VERSION 5.7 ;
  NOWIREEXTENSIONATPIN ON ;
  DIVIDERCHAR "/" ;
  BUSBITCHARS "[]" ;

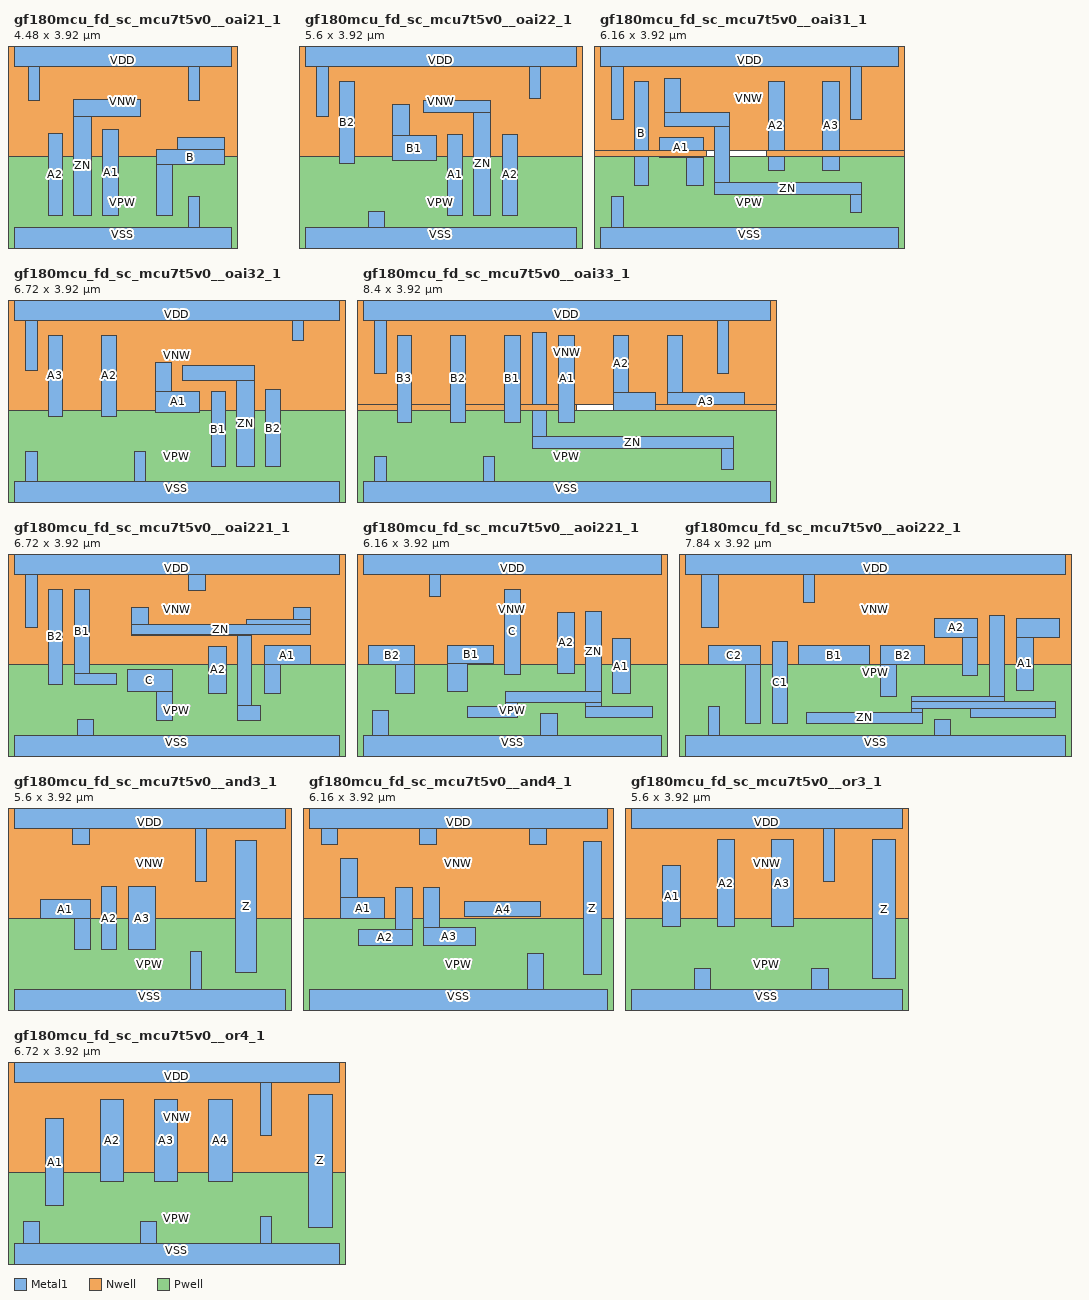
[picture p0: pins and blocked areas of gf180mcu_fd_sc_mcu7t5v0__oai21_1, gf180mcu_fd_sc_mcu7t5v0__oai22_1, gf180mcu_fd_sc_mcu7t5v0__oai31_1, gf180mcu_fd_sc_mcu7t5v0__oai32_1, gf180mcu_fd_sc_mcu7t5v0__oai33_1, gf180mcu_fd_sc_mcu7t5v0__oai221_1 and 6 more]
MACRO gf180mcu_fd_sc_mcu7t5v0__oai21_1
  CLASS core ;
  FOREIGN gf180mcu_fd_sc_mcu7t5v0__oai21_1 ;
  ORIGIN 0.000 0.000 ;
  SIZE 4.480 BY 3.920 ;
  SYMMETRY X Y ;
  SITE unithd ;
  PIN A1
    DIRECTION INPUT ;
    ANTENNAGATEAREA 1.102000 ;
    PORT
      LAYER Metal1 ;
        RECT 1.825 0.550 2.160 2.320 ;
    END
  END A1
  PIN A2
    DIRECTION INPUT ;
    ANTENNAGATEAREA 1.102000 ;
    PORT
      LAYER Metal1 ;
        RECT 0.705 0.550 1.000 2.230 ;
    END
  END A2
  PIN B
    DIRECTION INPUT ;
    ANTENNAGATEAREA 1.057000 ;
    PORT
      LAYER Metal1 ;
        RECT 3.375 1.900 4.350 2.150 ;
        RECT 2.945 1.600 4.350 1.900 ;
        RECT 2.945 0.550 3.280 1.600 ;
    END
  END B
  PIN ZN
    DIRECTION OUTPUT ;
    ANTENNADIFFAREA 1.276000 ;
    PORT
      LAYER Metal1 ;
        RECT 1.230 2.590 2.615 2.930 ;
        RECT 1.230 0.550 1.595 2.590 ;
    END
  END ZN
  PIN VDD
    DIRECTION INOUT ;
    USE POWER ;
    SHAPE ABUTMENT ;
    PORT
      LAYER Metal1 ;
        RECT 0.000 3.620 4.480 4.220 ;
        RECT 0.295 2.920 0.525 3.620 ;
        RECT 3.605 2.920 3.835 3.620 ;
    END
  END VDD
  PIN VNW
    DIRECTION INOUT ;
    USE POWER ;
    PORT
      LAYER Nwell ;
        RECT -0.430 1.760 4.910 4.350 ;
    END
  END VNW
  PIN VPW
    DIRECTION INOUT ;
    USE GROUND ;
    PORT
      LAYER Pwell ;
        RECT -0.430 -0.430 4.910 1.760 ;
    END
  END VPW
  PIN VSS
    DIRECTION INOUT ;
    USE GROUND ;
    SHAPE ABUTMENT ;
    PORT
      LAYER Metal1 ;
        RECT 3.605 0.300 3.835 0.930 ;
        RECT 0.000 -0.300 4.480 0.300 ;
    END
  END VSS
  OBS
      LAYER Metal1 ;
        RECT 0.755 3.160 3.075 3.390 ;
        RECT 0.755 2.690 0.985 3.160 ;
        RECT 0.245 2.460 0.985 2.690 ;
        RECT 0.245 0.550 0.475 2.460 ;
        RECT 2.845 2.360 3.075 3.160 ;
        RECT 2.485 2.130 3.075 2.360 ;
        RECT 2.485 0.550 2.715 2.130 ;
  END
END gf180mcu_fd_sc_mcu7t5v0__oai21_1

MACRO gf180mcu_fd_sc_mcu7t5v0__oai22_1
  CLASS core ;
  FOREIGN gf180mcu_fd_sc_mcu7t5v0__oai22_1 ;
  ORIGIN 0.000 0.000 ;
  SIZE 5.600 BY 3.920 ;
  SYMMETRY X Y ;
  SITE unithd ;
  PIN A1
    DIRECTION INPUT ;
    ANTENNAGATEAREA 1.102000 ;
    PORT
      LAYER Metal1 ;
        RECT 2.945 0.550 3.240 2.220 ;
    END
  END A1
  PIN A2
    DIRECTION INPUT ;
    ANTENNAGATEAREA 1.102000 ;
    PORT
      LAYER Metal1 ;
        RECT 4.065 0.550 4.380 2.220 ;
    END
  END A2
  PIN B1
    DIRECTION INPUT ;
    ANTENNAGATEAREA 1.102000 ;
    PORT
      LAYER Metal1 ;
        RECT 1.800 2.190 2.160 2.845 ;
        RECT 1.800 1.685 2.715 2.190 ;
    END
  END B1
  PIN B2
    DIRECTION INPUT ;
    ANTENNAGATEAREA 1.102000 ;
    PORT
      LAYER Metal1 ;
        RECT 0.705 1.610 1.030 3.320 ;
    END
  END B2
  PIN ZN
    DIRECTION OUTPUT ;
    ANTENNADIFFAREA 1.182800 ;
    PORT
      LAYER Metal1 ;
        RECT 2.440 2.680 3.835 2.910 ;
        RECT 3.480 0.550 3.835 2.680 ;
    END
  END ZN
  PIN VDD
    DIRECTION INOUT ;
    USE POWER ;
    SHAPE ABUTMENT ;
    PORT
      LAYER Metal1 ;
        RECT 0.000 3.620 5.600 4.220 ;
        RECT 0.245 2.590 0.475 3.620 ;
        RECT 4.625 2.960 4.855 3.620 ;
    END
  END VDD
  PIN VNW
    DIRECTION INOUT ;
    USE POWER ;
    PORT
      LAYER Nwell ;
        RECT -0.430 1.760 6.030 4.350 ;
    END
  END VNW
  PIN VPW
    DIRECTION INOUT ;
    USE GROUND ;
    PORT
      LAYER Pwell ;
        RECT -0.430 -0.430 6.030 1.760 ;
    END
  END VPW
  PIN VSS
    DIRECTION INOUT ;
    USE GROUND ;
    SHAPE ABUTMENT ;
    PORT
      LAYER Metal1 ;
        RECT 1.310 0.300 1.650 0.635 ;
        RECT 0.000 -0.300 5.600 0.300 ;
    END
  END VSS
  OBS
      LAYER Metal1 ;
        RECT 1.320 3.140 4.365 3.370 ;
        RECT 1.320 1.095 1.550 3.140 ;
        RECT 4.135 2.680 4.365 3.140 ;
        RECT 4.135 2.450 4.955 2.680 ;
        RECT 0.245 0.865 2.715 1.095 ;
        RECT 0.245 0.550 0.475 0.865 ;
        RECT 2.485 0.550 2.715 0.865 ;
        RECT 4.725 0.550 4.955 2.450 ;
  END
END gf180mcu_fd_sc_mcu7t5v0__oai22_1

MACRO gf180mcu_fd_sc_mcu7t5v0__oai31_1
  CLASS core ;
  FOREIGN gf180mcu_fd_sc_mcu7t5v0__oai31_1 ;
  ORIGIN 0.000 0.000 ;
  SIZE 6.160 BY 3.920 ;
  SYMMETRY X Y ;
  SITE unithd ;
  PIN A1
    DIRECTION INPUT ;
    ANTENNAGATEAREA 1.036500 ;
    PORT
      LAYER Metal1 ;
        RECT 1.230 1.750 2.130 2.150 ;
        RECT 1.790 1.160 2.130 1.750 ;
    END
  END A1
  PIN A2
    DIRECTION INPUT ;
    ANTENNAGATEAREA 1.036500 ;
    PORT
      LAYER Metal1 ;
        RECT 3.470 1.470 3.810 3.320 ;
    END
  END A2
  PIN A3
    DIRECTION INPUT ;
    ANTENNAGATEAREA 1.036500 ;
    PORT
      LAYER Metal1 ;
        RECT 4.590 1.470 4.935 3.320 ;
    END
  END A3
  PIN B
    DIRECTION INPUT ;
    ANTENNAGATEAREA 1.054000 ;
    PORT
      LAYER Metal1 ;
        RECT 0.705 1.160 1.000 3.320 ;
    END
  END B
  PIN ZN
    DIRECTION OUTPUT ;
    ANTENNADIFFAREA 1.988400 ;
    PORT
      LAYER Metal1 ;
        RECT 1.330 2.680 1.670 3.380 ;
        RECT 1.330 2.380 2.680 2.680 ;
        RECT 2.360 1.220 2.680 2.380 ;
        RECT 2.360 0.990 5.395 1.220 ;
        RECT 5.165 0.605 5.395 0.990 ;
    END
  END ZN
  PIN VDD
    DIRECTION INOUT ;
    USE POWER ;
    SHAPE ABUTMENT ;
    PORT
      LAYER Metal1 ;
        RECT 0.000 3.620 6.160 4.220 ;
        RECT 0.245 2.530 0.475 3.620 ;
        RECT 5.165 2.530 5.395 3.620 ;
    END
  END VDD
  PIN VNW
    DIRECTION INOUT ;
    USE POWER ;
    PORT
      LAYER Nwell ;
        RECT -0.430 1.885 6.590 4.350 ;
        RECT -0.430 1.760 2.195 1.885 ;
        RECT 3.440 1.760 6.590 1.885 ;
    END
  END VNW
  PIN VPW
    DIRECTION INOUT ;
    USE GROUND ;
    PORT
      LAYER Pwell ;
        RECT -0.430 -0.430 6.590 1.760 ;
    END
  END VPW
  PIN VSS
    DIRECTION INOUT ;
    USE GROUND ;
    SHAPE ABUTMENT ;
    PORT
      LAYER Metal1 ;
        RECT 0.245 0.300 0.475 0.945 ;
        RECT 0.000 -0.300 6.160 0.300 ;
    END
  END VSS
  OBS
      LAYER Metal1 ;
        RECT 1.310 0.530 4.330 0.760 ;
  END
END gf180mcu_fd_sc_mcu7t5v0__oai31_1

MACRO gf180mcu_fd_sc_mcu7t5v0__oai32_1
  CLASS core ;
  FOREIGN gf180mcu_fd_sc_mcu7t5v0__oai32_1 ;
  ORIGIN 0.000 0.000 ;
  SIZE 6.720 BY 3.920 ;
  SYMMETRY X Y ;
  SITE unithd ;
  PIN A1
    DIRECTION INPUT ;
    ANTENNAGATEAREA 1.102000 ;
    PORT
      LAYER Metal1 ;
        RECT 2.920 2.150 3.240 2.750 ;
        RECT 2.920 1.730 3.830 2.150 ;
    END
  END A1
  PIN A2
    DIRECTION INPUT ;
    ANTENNAGATEAREA 1.102000 ;
    PORT
      LAYER Metal1 ;
        RECT 1.800 1.650 2.120 3.310 ;
    END
  END A2
  PIN A3
    DIRECTION INPUT ;
    ANTENNAGATEAREA 1.102000 ;
    PORT
      LAYER Metal1 ;
        RECT 0.705 1.650 1.000 3.310 ;
    END
  END A3
  PIN B1
    DIRECTION INPUT ;
    ANTENNAGATEAREA 1.102000 ;
    PORT
      LAYER Metal1 ;
        RECT 4.065 0.610 4.370 2.150 ;
    END
  END B1
  PIN B2
    DIRECTION INPUT ;
    ANTENNAGATEAREA 1.102000 ;
    PORT
      LAYER Metal1 ;
        RECT 5.185 0.610 5.490 2.190 ;
    END
  END B2
  PIN ZN
    DIRECTION OUTPUT ;
    ANTENNADIFFAREA 1.304800 ;
    PORT
      LAYER Metal1 ;
        RECT 3.470 2.380 4.955 2.700 ;
        RECT 4.600 0.610 4.955 2.380 ;
    END
  END ZN
  PIN VDD
    DIRECTION INOUT ;
    USE POWER ;
    SHAPE ABUTMENT ;
    PORT
      LAYER Metal1 ;
        RECT 0.000 3.620 6.720 4.220 ;
        RECT 0.245 2.590 0.475 3.620 ;
        RECT 5.745 3.200 5.975 3.620 ;
    END
  END VDD
  PIN VNW
    DIRECTION INOUT ;
    USE POWER ;
    PORT
      LAYER Nwell ;
        RECT -0.430 1.760 7.150 4.350 ;
    END
  END VNW
  PIN VPW
    DIRECTION INOUT ;
    USE GROUND ;
    PORT
      LAYER Pwell ;
        RECT -0.430 -0.430 7.150 1.760 ;
    END
  END VPW
  PIN VSS
    DIRECTION INOUT ;
    USE GROUND ;
    SHAPE ABUTMENT ;
    PORT
      LAYER Metal1 ;
        RECT 0.245 0.300 0.475 0.915 ;
        RECT 2.485 0.300 2.715 0.915 ;
        RECT 0.000 -0.300 6.720 0.300 ;
    END
  END VSS
  OBS
      LAYER Metal1 ;
        RECT 2.450 3.050 5.450 3.280 ;
        RECT 2.450 1.400 2.680 3.050 ;
        RECT 5.220 2.870 5.450 3.050 ;
        RECT 5.220 2.640 6.075 2.870 ;
        RECT 1.365 1.165 3.835 1.400 ;
        RECT 1.365 0.610 1.595 1.165 ;
        RECT 3.605 0.610 3.835 1.165 ;
        RECT 5.845 0.610 6.075 2.640 ;
  END
END gf180mcu_fd_sc_mcu7t5v0__oai32_1

MACRO gf180mcu_fd_sc_mcu7t5v0__oai33_1
  CLASS core ;
  FOREIGN gf180mcu_fd_sc_mcu7t5v0__oai33_1 ;
  ORIGIN 0.000 0.000 ;
  SIZE 8.400 BY 3.920 ;
  SYMMETRY X Y ;
  SITE unithd ;
  PIN A1
    DIRECTION INPUT ;
    ANTENNAGATEAREA 1.039500 ;
    PORT
      LAYER Metal1 ;
        RECT 4.040 1.525 4.360 3.320 ;
    END
  END A1
  PIN A2
    DIRECTION INPUT ;
    ANTENNAGATEAREA 1.039500 ;
    PORT
      LAYER Metal1 ;
        RECT 5.160 2.140 5.480 3.320 ;
        RECT 5.160 1.770 6.040 2.140 ;
    END
  END A2
  PIN A3
    DIRECTION INPUT ;
    ANTENNAGATEAREA 1.039500 ;
    PORT
      LAYER Metal1 ;
        RECT 6.280 2.140 6.600 3.320 ;
        RECT 6.280 1.770 7.870 2.140 ;
    END
  END A3
  PIN B1
    DIRECTION INPUT ;
    ANTENNAGATEAREA 1.039500 ;
    PORT
      LAYER Metal1 ;
        RECT 2.920 1.525 3.240 3.320 ;
    END
  END B1
  PIN B2
    DIRECTION INPUT ;
    ANTENNAGATEAREA 1.039500 ;
    PORT
      LAYER Metal1 ;
        RECT 1.800 1.525 2.120 3.320 ;
    END
  END B2
  PIN B3
    DIRECTION INPUT ;
    ANTENNAGATEAREA 1.039500 ;
    PORT
      LAYER Metal1 ;
        RECT 0.705 1.525 1.000 3.320 ;
    END
  END B3
  PIN ZN
    DIRECTION OUTPUT ;
    ANTENNADIFFAREA 1.871900 ;
    PORT
      LAYER Metal1 ;
        RECT 3.490 1.220 3.790 3.380 ;
        RECT 3.490 0.990 7.635 1.220 ;
        RECT 7.405 0.555 7.635 0.990 ;
    END
  END ZN
  PIN VDD
    DIRECTION INOUT ;
    USE POWER ;
    SHAPE ABUTMENT ;
    PORT
      LAYER Metal1 ;
        RECT 0.000 3.620 8.400 4.220 ;
        RECT 0.245 2.530 0.475 3.620 ;
        RECT 7.305 2.530 7.535 3.620 ;
    END
  END VDD
  PIN VNW
    DIRECTION INOUT ;
    USE POWER ;
    PORT
      LAYER Nwell ;
        RECT -0.430 1.885 8.830 4.350 ;
        RECT -0.430 1.760 4.410 1.885 ;
        RECT 5.695 1.760 8.830 1.885 ;
    END
  END VNW
  PIN VPW
    DIRECTION INOUT ;
    USE GROUND ;
    PORT
      LAYER Pwell ;
        RECT -0.430 -0.430 8.830 1.760 ;
    END
  END VPW
  PIN VSS
    DIRECTION INOUT ;
    USE GROUND ;
    SHAPE ABUTMENT ;
    PORT
      LAYER Metal1 ;
        RECT 0.245 0.300 0.475 0.815 ;
        RECT 2.485 0.300 2.715 0.815 ;
        RECT 0.000 -0.300 8.400 0.300 ;
    END
  END VSS
  OBS
      LAYER Metal1 ;
        RECT 1.365 1.045 3.175 1.275 ;
        RECT 1.365 0.530 1.595 1.045 ;
        RECT 2.945 0.760 3.175 1.045 ;
        RECT 2.945 0.530 6.570 0.760 ;
  END
END gf180mcu_fd_sc_mcu7t5v0__oai33_1

MACRO gf180mcu_fd_sc_mcu7t5v0__oai221_1
  CLASS core ;
  FOREIGN gf180mcu_fd_sc_mcu7t5v0__oai221_1 ;
  ORIGIN 0.000 0.000 ;
  SIZE 6.720 BY 3.920 ;
  SYMMETRY X Y ;
  SITE unithd ;
  PIN A1
    DIRECTION INPUT ;
    ANTENNAGATEAREA 1.102000 ;
    PORT
      LAYER Metal1 ;
        RECT 5.160 1.770 6.110 2.150 ;
        RECT 5.160 1.170 5.500 1.770 ;
    END
  END A1
  PIN A2
    DIRECTION INPUT ;
    ANTENNAGATEAREA 1.102000 ;
    PORT
      LAYER Metal1 ;
        RECT 4.010 1.170 4.390 2.135 ;
    END
  END A2
  PIN B1
    DIRECTION INPUT ;
    ANTENNAGATEAREA 1.102000 ;
    PORT
      LAYER Metal1 ;
        RECT 1.240 1.575 1.560 3.320 ;
        RECT 1.240 1.345 2.110 1.575 ;
    END
  END B1
  PIN B2
    DIRECTION INPUT ;
    ANTENNAGATEAREA 1.102000 ;
    PORT
      LAYER Metal1 ;
        RECT 0.705 1.345 1.000 3.320 ;
    END
  END B2
  PIN C
    DIRECTION INPUT ;
    ANTENNAGATEAREA 0.964500 ;
    PORT
      LAYER Metal1 ;
        RECT 2.340 1.210 3.260 1.665 ;
        RECT 2.945 0.610 3.260 1.210 ;
    END
  END C
  PIN ZN
    DIRECTION OUTPUT ;
    ANTENNADIFFAREA 1.753600 ;
    PORT
      LAYER Metal1 ;
        RECT 2.430 2.595 2.770 2.930 ;
        RECT 5.770 2.700 6.110 2.930 ;
        RECT 4.795 2.595 6.110 2.700 ;
        RECT 2.430 2.380 6.110 2.595 ;
        RECT 2.430 2.365 4.910 2.380 ;
        RECT 4.620 0.910 4.910 2.365 ;
        RECT 4.620 0.610 5.095 0.910 ;
    END
  END ZN
  PIN VDD
    DIRECTION INOUT ;
    USE POWER ;
    SHAPE ABUTMENT ;
    PORT
      LAYER Metal1 ;
        RECT 0.000 3.620 6.720 4.220 ;
        RECT 0.245 2.530 0.475 3.620 ;
        RECT 3.610 3.285 3.950 3.620 ;
    END
  END VDD
  PIN VNW
    DIRECTION INOUT ;
    USE POWER ;
    PORT
      LAYER Nwell ;
        RECT -0.430 1.760 7.150 4.350 ;
    END
  END VNW
  PIN VPW
    DIRECTION INOUT ;
    USE GROUND ;
    PORT
      LAYER Pwell ;
        RECT -0.430 -0.430 7.150 1.760 ;
    END
  END VPW
  PIN VSS
    DIRECTION INOUT ;
    USE GROUND ;
    SHAPE ABUTMENT ;
    PORT
      LAYER Metal1 ;
        RECT 1.310 0.300 1.650 0.635 ;
        RECT 0.000 -0.300 6.720 0.300 ;
    END
  END VSS
  OBS
      LAYER Metal1 ;
        RECT 1.950 3.160 3.360 3.390 ;
        RECT 1.950 2.135 2.180 3.160 ;
        RECT 3.130 3.055 3.360 3.160 ;
        RECT 4.290 3.160 6.570 3.390 ;
        RECT 4.290 3.055 4.520 3.160 ;
        RECT 3.130 2.825 4.520 3.055 ;
        RECT 1.950 1.905 3.770 2.135 ;
        RECT 0.245 0.965 2.110 1.095 ;
        RECT 0.245 0.865 2.715 0.965 ;
        RECT 0.245 0.625 0.475 0.865 ;
        RECT 1.880 0.625 2.715 0.865 ;
        RECT 3.540 0.910 3.770 1.905 ;
        RECT 6.340 0.910 6.570 3.160 ;
        RECT 3.540 0.680 3.950 0.910 ;
        RECT 5.870 0.680 6.570 0.910 ;
  END
END gf180mcu_fd_sc_mcu7t5v0__oai221_1

MACRO gf180mcu_fd_sc_mcu7t5v0__aoi221_1
  CLASS core ;
  FOREIGN gf180mcu_fd_sc_mcu7t5v0__aoi221_1 ;
  ORIGIN 0.000 0.000 ;
  SIZE 6.160 BY 3.920 ;
  SYMMETRY X Y ;
  SITE unithd ;
  PIN A1
    DIRECTION INPUT ;
    ANTENNAGATEAREA 1.033500 ;
    PORT
      LAYER Metal1 ;
        RECT 5.150 1.160 5.510 2.300 ;
    END
  END A1
  PIN A2
    DIRECTION INPUT ;
    ANTENNAGATEAREA 1.033500 ;
    PORT
      LAYER Metal1 ;
        RECT 4.005 1.585 4.370 2.835 ;
    END
  END A2
  PIN B1
    DIRECTION INPUT ;
    ANTENNAGATEAREA 1.033500 ;
    PORT
      LAYER Metal1 ;
        RECT 1.750 1.780 2.690 2.150 ;
        RECT 1.750 1.210 2.150 1.780 ;
    END
  END B1
  PIN B2
    DIRECTION INPUT ;
    ANTENNAGATEAREA 1.033500 ;
    PORT
      LAYER Metal1 ;
        RECT 0.120 1.770 1.070 2.150 ;
        RECT 0.680 1.160 1.070 1.770 ;
    END
  END B2
  PIN C
    DIRECTION INPUT ;
    ANTENNAGATEAREA 0.886500 ;
    PORT
      LAYER Metal1 ;
        RECT 2.920 1.550 3.240 3.320 ;
    END
  END C
  PIN ZN
    DIRECTION OUTPUT ;
    ANTENNADIFFAREA 1.489200 ;
    PORT
      LAYER Metal1 ;
        RECT 4.600 1.205 4.920 2.865 ;
        RECT 2.950 0.975 4.920 1.205 ;
        RECT 2.950 0.905 3.180 0.975 ;
        RECT 2.150 0.675 3.180 0.905 ;
        RECT 4.600 0.905 4.920 0.975 ;
        RECT 4.600 0.675 5.980 0.905 ;
    END
  END ZN
  PIN VDD
    DIRECTION INOUT ;
    USE POWER ;
    SHAPE ABUTMENT ;
    PORT
      LAYER Metal1 ;
        RECT 0.000 3.620 6.160 4.220 ;
        RECT 1.365 3.160 1.595 3.620 ;
    END
  END VDD
  PIN VNW
    DIRECTION INOUT ;
    USE POWER ;
    PORT
      LAYER Nwell ;
        RECT -0.430 1.760 6.590 4.350 ;
    END
  END VNW
  PIN VPW
    DIRECTION INOUT ;
    USE GROUND ;
    PORT
      LAYER Pwell ;
        RECT -0.430 -0.430 6.590 1.760 ;
    END
  END VPW
  PIN VSS
    DIRECTION INOUT ;
    USE GROUND ;
    SHAPE ABUTMENT ;
    PORT
      LAYER Metal1 ;
        RECT 0.190 0.300 0.530 0.815 ;
        RECT 3.670 0.300 4.010 0.745 ;
        RECT 0.000 -0.300 6.160 0.300 ;
    END
  END VSS
  OBS
      LAYER Metal1 ;
        RECT 0.280 2.930 0.630 3.380 ;
        RECT 2.330 2.930 2.670 3.380 ;
        RECT 0.280 2.590 2.670 2.930 ;
        RECT 3.545 3.150 5.915 3.380 ;
        RECT 3.545 2.530 3.775 3.150 ;
        RECT 5.685 2.530 5.915 3.150 ;
  END
END gf180mcu_fd_sc_mcu7t5v0__aoi221_1

MACRO gf180mcu_fd_sc_mcu7t5v0__aoi222_1
  CLASS core ;
  FOREIGN gf180mcu_fd_sc_mcu7t5v0__aoi222_1 ;
  ORIGIN 0.000 0.000 ;
  SIZE 7.840 BY 3.920 ;
  SYMMETRY X Y ;
  SITE unithd ;
  PIN A1
    DIRECTION INPUT ;
    ANTENNAGATEAREA 1.072000 ;
    PORT
      LAYER Metal1 ;
        RECT 6.840 2.330 7.720 2.710 ;
        RECT 6.840 1.230 7.180 2.330 ;
    END
  END A1
  PIN A2
    DIRECTION INPUT ;
    ANTENNAGATEAREA 1.072000 ;
    PORT
      LAYER Metal1 ;
        RECT 5.140 2.330 6.040 2.710 ;
        RECT 5.720 1.535 6.040 2.330 ;
    END
  END A2
  PIN B1
    DIRECTION INPUT ;
    ANTENNAGATEAREA 1.072000 ;
    PORT
      LAYER Metal1 ;
        RECT 2.350 1.770 3.800 2.150 ;
    END
  END B1
  PIN B2
    DIRECTION INPUT ;
    ANTENNAGATEAREA 1.072000 ;
    PORT
      LAYER Metal1 ;
        RECT 4.040 1.770 4.950 2.150 ;
        RECT 4.040 1.105 4.360 1.770 ;
    END
  END B2
  PIN C1
    DIRECTION INPUT ;
    ANTENNAGATEAREA 1.072000 ;
    PORT
      LAYER Metal1 ;
        RECT 1.800 0.550 2.120 2.235 ;
    END
  END C1
  PIN C2
    DIRECTION INPUT ;
    ANTENNAGATEAREA 1.072000 ;
    PORT
      LAYER Metal1 ;
        RECT 0.480 1.770 1.560 2.150 ;
        RECT 1.240 0.550 1.560 1.770 ;
    END
  END C2
  PIN ZN
    DIRECTION OUTPUT ;
    ANTENNADIFFAREA 1.756500 ;
    PORT
      LAYER Metal1 ;
        RECT 6.280 1.095 6.600 2.770 ;
        RECT 4.665 1.000 6.600 1.095 ;
        RECT 4.665 0.865 7.635 1.000 ;
        RECT 4.665 0.780 4.895 0.865 ;
        RECT 2.510 0.550 4.895 0.780 ;
        RECT 5.880 0.670 7.635 0.865 ;
    END
  END ZN
  PIN VDD
    DIRECTION INOUT ;
    USE POWER ;
    SHAPE ABUTMENT ;
    PORT
      LAYER Metal1 ;
        RECT 0.000 3.620 7.840 4.220 ;
        RECT 0.345 2.530 0.685 3.620 ;
        RECT 2.440 3.040 2.670 3.620 ;
    END
  END VDD
  PIN VNW
    DIRECTION INOUT ;
    USE POWER ;
    PORT
      LAYER Nwell ;
        RECT -0.430 1.760 8.270 4.350 ;
    END
  END VNW
  PIN VPW
    DIRECTION INOUT ;
    USE GROUND ;
    PORT
      LAYER Pwell ;
        RECT -0.430 -0.430 8.270 1.760 ;
    END
  END VPW
  PIN VSS
    DIRECTION INOUT ;
    USE GROUND ;
    SHAPE ABUTMENT ;
    PORT
      LAYER Metal1 ;
        RECT 0.480 0.300 0.710 0.905 ;
        RECT 5.145 0.300 5.485 0.635 ;
        RECT 0.000 -0.300 7.840 0.300 ;
    END
  END VSS
  OBS
      LAYER Metal1 ;
        RECT 1.365 2.760 1.705 3.380 ;
        RECT 3.095 3.095 7.635 3.325 ;
        RECT 1.365 2.530 4.500 2.760 ;
  END
END gf180mcu_fd_sc_mcu7t5v0__aoi222_1

MACRO gf180mcu_fd_sc_mcu7t5v0__and3_1
  CLASS core ;
  FOREIGN gf180mcu_fd_sc_mcu7t5v0__and3_1 ;
  ORIGIN 0.000 0.000 ;
  SIZE 5.600 BY 3.920 ;
  SYMMETRY X Y ;
  SITE unithd ;
  PIN A1
    DIRECTION INPUT ;
    ANTENNAGATEAREA 0.495500 ;
    PORT
      LAYER Metal1 ;
        RECT 0.540 1.770 1.570 2.150 ;
        RECT 1.250 1.120 1.570 1.770 ;
    END
  END A1
  PIN A2
    DIRECTION INPUT ;
    ANTENNAGATEAREA 0.495500 ;
    PORT
      LAYER Metal1 ;
        RECT 1.800 1.120 2.120 2.415 ;
    END
  END A2
  PIN A3
    DIRECTION INPUT ;
    ANTENNAGATEAREA 0.495500 ;
    PORT
      LAYER Metal1 ;
        RECT 2.360 1.120 2.910 2.415 ;
    END
  END A3
  PIN Z
    DIRECTION OUTPUT ;
    ANTENNADIFFAREA 0.875600 ;
    PORT
      LAYER Metal1 ;
        RECT 4.570 0.650 5.010 3.380 ;
    END
  END Z
  PIN VDD
    DIRECTION INOUT ;
    USE POWER ;
    SHAPE ABUTMENT ;
    PORT
      LAYER Metal1 ;
        RECT 0.000 3.620 5.600 4.220 ;
        RECT 1.210 3.285 1.550 3.620 ;
        RECT 3.745 2.530 3.975 3.620 ;
    END
  END VDD
  PIN VNW
    DIRECTION INOUT ;
    USE POWER ;
    PORT
      LAYER Nwell ;
        RECT -0.430 1.760 6.030 4.350 ;
    END
  END VNW
  PIN VPW
    DIRECTION INOUT ;
    USE GROUND ;
    PORT
      LAYER Pwell ;
        RECT -0.430 -0.430 6.030 1.760 ;
    END
  END VPW
  PIN VSS
    DIRECTION INOUT ;
    USE GROUND ;
    SHAPE ABUTMENT ;
    PORT
      LAYER Metal1 ;
        RECT 3.645 0.300 3.875 1.090 ;
        RECT 0.000 -0.300 5.600 0.300 ;
    END
  END VSS
  OBS
      LAYER Metal1 ;
        RECT 0.190 3.055 0.530 3.340 ;
        RECT 2.230 3.055 2.570 3.340 ;
        RECT 0.190 2.825 3.415 3.055 ;
        RECT 3.185 1.800 3.415 2.825 ;
        RECT 3.185 1.460 4.315 1.800 ;
        RECT 0.190 0.805 0.530 1.035 ;
        RECT 3.185 0.805 3.415 1.460 ;
        RECT 0.190 0.575 3.415 0.805 ;
  END
END gf180mcu_fd_sc_mcu7t5v0__and3_1

MACRO gf180mcu_fd_sc_mcu7t5v0__and4_1
  CLASS core ;
  FOREIGN gf180mcu_fd_sc_mcu7t5v0__and4_1 ;
  ORIGIN 0.000 0.000 ;
  SIZE 6.160 BY 3.920 ;
  SYMMETRY X Y ;
  SITE unithd ;
  PIN A1
    DIRECTION INPUT ;
    ANTENNAGATEAREA 0.552000 ;
    PORT
      LAYER Metal1 ;
        RECT 0.660 2.190 1.000 3.000 ;
        RECT 0.660 1.770 1.560 2.190 ;
    END
  END A1
  PIN A2
    DIRECTION INPUT ;
    ANTENNAGATEAREA 0.552000 ;
    PORT
      LAYER Metal1 ;
        RECT 1.790 1.540 2.130 2.410 ;
        RECT 1.015 1.210 2.130 1.540 ;
    END
  END A2
  PIN A3
    DIRECTION INPUT ;
    ANTENNAGATEAREA 0.552000 ;
    PORT
      LAYER Metal1 ;
        RECT 2.360 1.570 2.700 2.410 ;
        RECT 2.360 1.210 3.430 1.570 ;
    END
  END A3
  PIN A4
    DIRECTION INPUT ;
    ANTENNAGATEAREA 0.552000 ;
    PORT
      LAYER Metal1 ;
        RECT 3.215 1.800 4.780 2.120 ;
    END
  END A4
  PIN Z
    DIRECTION OUTPUT ;
    ANTENNADIFFAREA 0.895400 ;
    PORT
      LAYER Metal1 ;
        RECT 5.660 0.610 6.030 3.350 ;
    END
  END Z
  PIN VDD
    DIRECTION INOUT ;
    USE POWER ;
    SHAPE ABUTMENT ;
    PORT
      LAYER Metal1 ;
        RECT 0.000 3.620 6.160 4.220 ;
        RECT 0.250 3.285 0.590 3.620 ;
        RECT 2.290 3.285 2.630 3.620 ;
        RECT 4.550 3.285 4.890 3.620 ;
    END
  END VDD
  PIN VNW
    DIRECTION INOUT ;
    USE POWER ;
    PORT
      LAYER Nwell ;
        RECT -0.430 1.760 6.590 4.350 ;
    END
  END VNW
  PIN VPW
    DIRECTION INOUT ;
    USE GROUND ;
    PORT
      LAYER Pwell ;
        RECT -0.430 -0.430 6.590 1.760 ;
    END
  END VPW
  PIN VSS
    DIRECTION INOUT ;
    USE GROUND ;
    SHAPE ABUTMENT ;
    PORT
      LAYER Metal1 ;
        RECT 4.505 0.300 4.845 1.035 ;
        RECT 0.000 -0.300 6.160 0.300 ;
    END
  END VSS
  OBS
      LAYER Metal1 ;
        RECT 1.270 3.055 1.610 3.390 ;
        RECT 3.310 3.055 3.650 3.390 ;
        RECT 1.270 2.825 5.385 3.055 ;
        RECT 5.155 1.505 5.385 2.825 ;
        RECT 3.770 1.265 5.385 1.505 ;
        RECT 0.305 0.760 0.535 1.090 ;
        RECT 3.770 0.760 4.000 1.265 ;
        RECT 0.305 0.530 4.000 0.760 ;
  END
END gf180mcu_fd_sc_mcu7t5v0__and4_1

MACRO gf180mcu_fd_sc_mcu7t5v0__or3_1
  CLASS core ;
  FOREIGN gf180mcu_fd_sc_mcu7t5v0__or3_1 ;
  ORIGIN 0.000 0.000 ;
  SIZE 5.600 BY 3.920 ;
  SYMMETRY X Y ;
  SITE unithd ;
  PIN A1
    DIRECTION INPUT ;
    ANTENNAGATEAREA 0.520000 ;
    PORT
      LAYER Metal1 ;
        RECT 0.660 1.595 1.020 2.855 ;
    END
  END A1
  PIN A2
    DIRECTION INPUT ;
    ANTENNAGATEAREA 0.520000 ;
    PORT
      LAYER Metal1 ;
        RECT 1.780 1.595 2.140 3.390 ;
    END
  END A2
  PIN A3
    DIRECTION INPUT ;
    ANTENNAGATEAREA 0.520000 ;
    PORT
      LAYER Metal1 ;
        RECT 2.900 1.595 3.350 3.390 ;
    END
  END A3
  PIN Z
    DIRECTION OUTPUT ;
    ANTENNADIFFAREA 0.897600 ;
    PORT
      LAYER Metal1 ;
        RECT 4.985 0.530 5.455 3.390 ;
    END
  END Z
  PIN VDD
    DIRECTION INOUT ;
    USE POWER ;
    SHAPE ABUTMENT ;
    PORT
      LAYER Metal1 ;
        RECT 0.000 3.620 5.600 4.220 ;
        RECT 3.965 2.530 4.195 3.620 ;
    END
  END VDD
  PIN VNW
    DIRECTION INOUT ;
    USE POWER ;
    PORT
      LAYER Nwell ;
        RECT -0.430 1.760 6.030 4.350 ;
    END
  END VNW
  PIN VPW
    DIRECTION INOUT ;
    USE GROUND ;
    PORT
      LAYER Pwell ;
        RECT -0.430 -0.430 6.030 1.760 ;
    END
  END VPW
  PIN VSS
    DIRECTION INOUT ;
    USE GROUND ;
    SHAPE ABUTMENT ;
    PORT
      LAYER Metal1 ;
        RECT 1.310 0.300 1.650 0.735 ;
        RECT 3.730 0.300 4.070 0.735 ;
        RECT 0.000 -0.300 5.600 0.300 ;
    END
  END VSS
  OBS
      LAYER Metal1 ;
        RECT 0.180 3.160 1.515 3.390 ;
        RECT 1.285 1.200 1.515 3.160 ;
        RECT 4.445 1.200 4.675 2.220 ;
        RECT 0.190 0.965 4.675 1.200 ;
        RECT 0.190 0.530 0.530 0.965 ;
        RECT 2.430 0.530 2.770 0.965 ;
  END
END gf180mcu_fd_sc_mcu7t5v0__or3_1

MACRO gf180mcu_fd_sc_mcu7t5v0__or4_1
  CLASS core ;
  FOREIGN gf180mcu_fd_sc_mcu7t5v0__or4_1 ;
  ORIGIN 0.000 0.000 ;
  SIZE 6.720 BY 3.920 ;
  SYMMETRY X Y ;
  SITE unithd ;
  PIN A1
    DIRECTION INPUT ;
    ANTENNAGATEAREA 0.496000 ;
    PORT
      LAYER Metal1 ;
        RECT 0.660 1.085 1.020 2.870 ;
    END
  END A1
  PIN A2
    DIRECTION INPUT ;
    ANTENNAGATEAREA 0.496000 ;
    PORT
      LAYER Metal1 ;
        RECT 1.780 1.580 2.260 3.280 ;
    END
  END A2
  PIN A3
    DIRECTION INPUT ;
    ANTENNAGATEAREA 0.496000 ;
    PORT
      LAYER Metal1 ;
        RECT 2.900 1.580 3.380 3.280 ;
    END
  END A3
  PIN A4
    DIRECTION INPUT ;
    ANTENNAGATEAREA 0.496000 ;
    PORT
      LAYER Metal1 ;
        RECT 4.020 1.580 4.500 3.280 ;
    END
  END A4
  PIN Z
    DIRECTION OUTPUT ;
    ANTENNADIFFAREA 0.897600 ;
    PORT
      LAYER Metal1 ;
        RECT 6.070 0.630 6.575 3.380 ;
    END
  END Z
  PIN VDD
    DIRECTION INOUT ;
    USE POWER ;
    SHAPE ABUTMENT ;
    PORT
      LAYER Metal1 ;
        RECT 0.000 3.620 6.720 4.220 ;
        RECT 5.085 2.530 5.315 3.620 ;
    END
  END VDD
  PIN VNW
    DIRECTION INOUT ;
    USE POWER ;
    PORT
      LAYER Nwell ;
        RECT -0.430 1.760 7.150 4.350 ;
    END
  END VNW
  PIN VPW
    DIRECTION INOUT ;
    USE GROUND ;
    PORT
      LAYER Pwell ;
        RECT -0.430 -0.430 7.150 1.760 ;
    END
  END VPW
  PIN VSS
    DIRECTION INOUT ;
    USE GROUND ;
    SHAPE ABUTMENT ;
    PORT
      LAYER Metal1 ;
        RECT 0.190 0.300 0.530 0.760 ;
        RECT 2.610 0.300 2.950 0.760 ;
        RECT 5.085 0.300 5.315 0.855 ;
        RECT 0.000 -0.300 6.720 0.300 ;
    END
  END VSS
  OBS
      LAYER Metal1 ;
        RECT 0.280 3.120 1.530 3.350 ;
        RECT 1.300 1.330 1.530 3.120 ;
        RECT 5.515 1.330 5.765 2.270 ;
        RECT 1.300 1.095 5.765 1.330 ;
        RECT 1.490 0.530 1.830 1.095 ;
        RECT 3.730 0.530 4.070 1.095 ;
  END
END gf180mcu_fd_sc_mcu7t5v0__or4_1

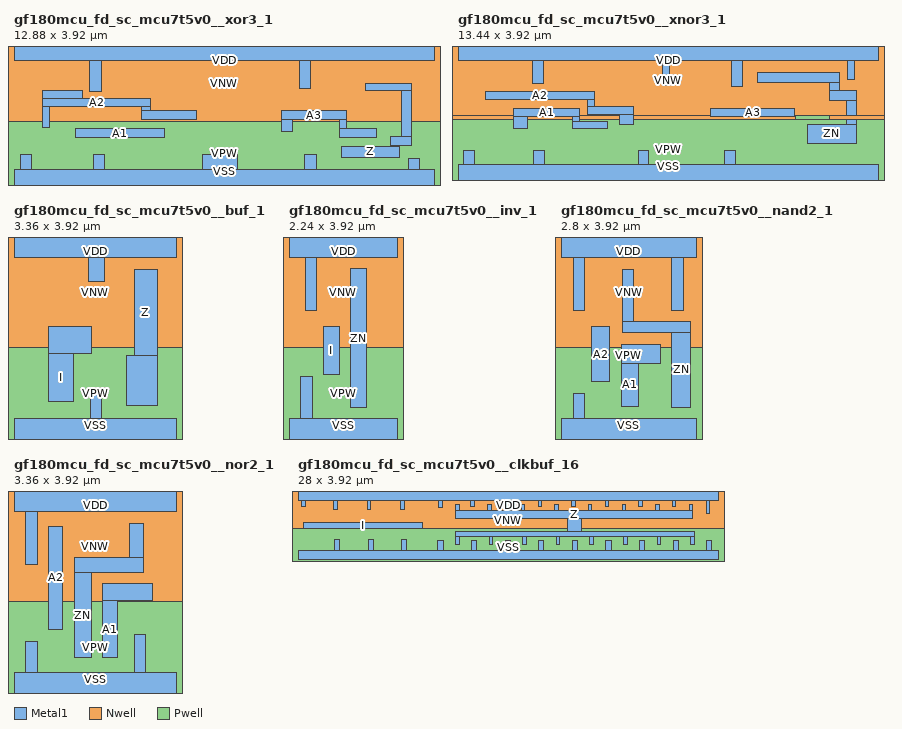
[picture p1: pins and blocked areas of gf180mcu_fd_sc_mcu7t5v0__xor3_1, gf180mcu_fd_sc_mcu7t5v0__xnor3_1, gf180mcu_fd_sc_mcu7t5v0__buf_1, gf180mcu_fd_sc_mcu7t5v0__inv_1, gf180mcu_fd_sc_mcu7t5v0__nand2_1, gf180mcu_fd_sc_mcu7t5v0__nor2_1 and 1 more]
MACRO gf180mcu_fd_sc_mcu7t5v0__xor3_1
  CLASS core ;
  FOREIGN gf180mcu_fd_sc_mcu7t5v0__xor3_1 ;
  ORIGIN 0.000 0.000 ;
  SIZE 12.880 BY 3.920 ;
  SYMMETRY X Y ;
  SITE unithd ;
  PIN A1
    DIRECTION INPUT ;
    ANTENNAGATEAREA 0.894500 ;
    PORT
      LAYER Metal1 ;
        RECT 1.890 1.265 4.600 1.535 ;
    END
  END A1
  PIN A2
    DIRECTION INPUT ;
    ANTENNAGATEAREA 0.894500 ;
    PORT
      LAYER Metal1 ;
        RECT 0.865 2.455 2.100 2.710 ;
        RECT 0.865 2.225 4.195 2.455 ;
        RECT 0.865 1.570 1.095 2.225 ;
        RECT 3.915 2.095 4.195 2.225 ;
        RECT 3.915 1.820 5.600 2.095 ;
    END
  END A2
  PIN A3
    DIRECTION INPUT ;
    ANTENNAGATEAREA 1.600500 ;
    PORT
      LAYER Metal1 ;
        RECT 8.205 1.825 10.205 2.100 ;
        RECT 8.205 1.455 8.545 1.825 ;
        RECT 9.975 1.560 10.205 1.825 ;
        RECT 9.975 1.265 11.110 1.560 ;
    END
  END A3
  PIN Z
    DIRECTION OUTPUT ;
    ANTENNADIFFAREA 1.060800 ;
    PORT
      LAYER Metal1 ;
        RECT 10.770 2.700 12.200 2.930 ;
        RECT 11.880 1.295 12.200 2.700 ;
        RECT 11.560 1.015 12.200 1.295 ;
        RECT 11.560 1.000 11.830 1.015 ;
        RECT 10.045 0.670 11.830 1.000 ;
    END
  END Z
  PIN VDD
    DIRECTION INOUT ;
    USE POWER ;
    SHAPE ABUTMENT ;
    PORT
      LAYER Metal1 ;
        RECT 0.000 3.620 12.880 4.220 ;
        RECT 2.330 2.685 2.670 3.620 ;
        RECT 8.750 2.790 9.090 3.620 ;
    END
  END VDD
  PIN VNW
    DIRECTION INOUT ;
    USE POWER ;
    PORT
      LAYER Nwell ;
        RECT -0.430 1.760 13.310 4.350 ;
    END
  END VNW
  PIN VPW
    DIRECTION INOUT ;
    USE GROUND ;
    PORT
      LAYER Pwell ;
        RECT -0.430 -0.430 13.310 1.760 ;
    END
  END VPW
  PIN VSS
    DIRECTION INOUT ;
    USE GROUND ;
    SHAPE ABUTMENT ;
    PORT
      LAYER Metal1 ;
        RECT 0.190 0.300 0.530 0.760 ;
        RECT 2.430 0.300 2.770 0.760 ;
        RECT 5.770 0.300 6.850 0.760 ;
        RECT 8.915 0.300 9.275 0.760 ;
        RECT 12.085 0.300 12.425 0.635 ;
        RECT 0.000 -0.300 12.880 0.300 ;
    END
  END VSS
  OBS
      LAYER Metal1 ;
        RECT 3.730 3.160 6.055 3.390 ;
        RECT 0.345 1.305 0.575 2.980 ;
        RECT 3.730 2.755 4.070 3.160 ;
        RECT 4.750 2.555 5.090 2.915 ;
        RECT 5.825 2.815 6.055 3.160 ;
        RECT 6.285 3.160 7.925 3.390 ;
        RECT 9.640 3.160 12.160 3.390 ;
        RECT 6.285 2.555 6.515 3.160 ;
        RECT 4.750 2.325 6.515 2.555 ;
        RECT 1.385 1.765 3.510 1.995 ;
        RECT 1.385 1.305 1.650 1.765 ;
        RECT 5.880 1.305 6.110 2.325 ;
        RECT 6.745 1.765 6.975 2.925 ;
        RECT 7.695 2.560 7.925 3.160 ;
        RECT 7.695 2.470 10.585 2.560 ;
        RECT 7.695 2.330 11.585 2.470 ;
        RECT 10.395 2.240 11.585 2.330 ;
        RECT 6.745 1.535 7.930 1.765 ;
        RECT 11.350 1.760 11.585 2.240 ;
        RECT 0.345 1.070 1.650 1.305 ;
        RECT 1.310 0.530 1.650 1.070 ;
        RECT 5.195 1.070 7.390 1.305 ;
        RECT 7.625 1.220 7.930 1.535 ;
        RECT 9.395 1.220 9.745 1.555 ;
        RECT 5.195 0.760 5.425 1.070 ;
        RECT 3.700 0.530 5.425 0.760 ;
        RECT 7.625 0.990 9.745 1.220 ;
        RECT 7.625 0.530 7.965 0.990 ;
  END
END gf180mcu_fd_sc_mcu7t5v0__xor3_1

MACRO gf180mcu_fd_sc_mcu7t5v0__xnor3_1
  CLASS core ;
  FOREIGN gf180mcu_fd_sc_mcu7t5v0__xnor3_1 ;
  ORIGIN 0.000 0.000 ;
  SIZE 13.440 BY 3.920 ;
  SYMMETRY X Y ;
  SITE unithd ;
  PIN A1
    DIRECTION INPUT ;
    ANTENNAGATEAREA 0.892000 ;
    PORT
      LAYER Metal1 ;
        RECT 1.770 1.825 3.900 2.095 ;
        RECT 1.770 1.455 2.225 1.825 ;
        RECT 3.670 1.690 3.900 1.825 ;
        RECT 3.670 1.455 4.770 1.690 ;
    END
  END A1
  PIN A2
    DIRECTION INPUT ;
    ANTENNAGATEAREA 0.892000 ;
    PORT
      LAYER Metal1 ;
        RECT 0.870 2.385 4.360 2.655 ;
        RECT 4.130 2.150 4.360 2.385 ;
        RECT 4.130 1.920 5.620 2.150 ;
        RECT 5.175 1.595 5.620 1.920 ;
    END
  END A2
  PIN A3
    DIRECTION INPUT ;
    ANTENNAGATEAREA 1.535500 ;
    PORT
      LAYER Metal1 ;
        RECT 8.085 1.825 10.765 2.095 ;
    END
  END A3
  PIN ZN
    DIRECTION OUTPUT ;
    ANTENNADIFFAREA 1.511100 ;
    PORT
      LAYER Metal1 ;
        RECT 9.570 2.920 12.215 3.240 ;
        RECT 11.880 2.680 12.215 2.920 ;
        RECT 11.880 2.360 12.760 2.680 ;
        RECT 12.440 1.580 12.760 2.360 ;
        RECT 11.170 0.990 12.760 1.580 ;
    END
  END ZN
  PIN VDD
    DIRECTION INOUT ;
    USE POWER ;
    SHAPE ABUTMENT ;
    PORT
      LAYER Metal1 ;
        RECT 0.000 3.620 13.440 4.220 ;
        RECT 2.370 2.900 2.730 3.620 ;
        RECT 6.545 2.840 6.775 3.620 ;
        RECT 8.760 2.815 9.100 3.620 ;
        RECT 12.465 3.015 12.695 3.620 ;
    END
  END VDD
  PIN VNW
    DIRECTION INOUT ;
    USE POWER ;
    PORT
      LAYER Nwell ;
        RECT -0.430 1.885 13.870 4.350 ;
        RECT -0.430 1.760 10.790 1.885 ;
        RECT 11.890 1.760 13.870 1.885 ;
    END
  END VNW
  PIN VPW
    DIRECTION INOUT ;
    USE GROUND ;
    PORT
      LAYER Pwell ;
        RECT 10.790 1.760 11.890 1.885 ;
        RECT -0.430 -0.430 13.870 1.760 ;
    END
  END VPW
  PIN VSS
    DIRECTION INOUT ;
    USE GROUND ;
    SHAPE ABUTMENT ;
    PORT
      LAYER Metal1 ;
        RECT 0.190 0.300 0.530 0.760 ;
        RECT 2.430 0.300 2.770 0.760 ;
        RECT 5.770 0.300 6.110 0.760 ;
        RECT 8.530 0.300 8.870 0.760 ;
        RECT 0.000 -0.300 13.440 0.300 ;
    END
  END VSS
  OBS
      LAYER Metal1 ;
        RECT 0.345 1.220 0.575 3.195 ;
        RECT 3.720 3.160 6.120 3.390 ;
        RECT 3.720 2.900 4.080 3.160 ;
        RECT 4.740 2.610 5.100 2.930 ;
        RECT 5.760 2.900 6.120 3.160 ;
        RECT 7.030 3.160 8.500 3.390 ;
        RECT 7.030 2.610 7.260 3.160 ;
        RECT 4.740 2.380 7.260 2.610 ;
        RECT 5.880 1.225 6.110 2.380 ;
        RECT 7.030 1.535 7.260 2.380 ;
        RECT 7.510 1.225 7.850 2.930 ;
        RECT 8.270 2.565 8.500 3.160 ;
        RECT 8.270 2.330 11.450 2.565 ;
        RECT 11.220 2.095 11.450 2.330 ;
        RECT 11.220 1.860 12.170 2.095 ;
        RECT 9.200 1.225 9.540 1.565 ;
        RECT 0.345 0.990 3.495 1.220 ;
        RECT 3.730 0.990 6.110 1.225 ;
        RECT 6.490 0.990 9.540 1.225 ;
        RECT 1.305 0.530 1.650 0.990 ;
        RECT 3.730 0.530 4.070 0.990 ;
        RECT 6.490 0.530 6.830 0.990 ;
        RECT 9.740 0.530 12.860 0.760 ;
  END
END gf180mcu_fd_sc_mcu7t5v0__xnor3_1

MACRO gf180mcu_fd_sc_mcu7t5v0__buf_1
  CLASS core ;
  FOREIGN gf180mcu_fd_sc_mcu7t5v0__buf_1 ;
  ORIGIN 0.000 0.000 ;
  SIZE 3.360 BY 3.920 ;
  SYMMETRY X Y ;
  SITE unithd ;
  PIN I
    DIRECTION INPUT ;
    ANTENNAGATEAREA 0.498500 ;
    PORT
      LAYER Metal1 ;
        RECT 0.705 1.630 1.590 2.190 ;
        RECT 0.705 0.650 1.220 1.630 ;
    END
  END I
  PIN Z
    DIRECTION OUTPUT ;
    ANTENNADIFFAREA 0.897600 ;
    PORT
      LAYER Metal1 ;
        RECT 2.485 1.600 2.955 3.380 ;
        RECT 2.330 0.575 2.955 1.600 ;
    END
  END Z
  PIN VDD
    DIRECTION INOUT ;
    USE POWER ;
    SHAPE ABUTMENT ;
    PORT
      LAYER Metal1 ;
        RECT 0.000 3.620 3.360 4.220 ;
        RECT 1.530 3.130 1.870 3.620 ;
    END
  END VDD
  PIN VNW
    DIRECTION INOUT ;
    USE POWER ;
    PORT
      LAYER Nwell ;
        RECT -0.430 1.760 3.790 4.350 ;
    END
  END VNW
  PIN VPW
    DIRECTION INOUT ;
    USE GROUND ;
    PORT
      LAYER Pwell ;
        RECT -0.430 -0.430 3.790 1.760 ;
    END
  END VPW
  PIN VSS
    DIRECTION INOUT ;
    USE GROUND ;
    SHAPE ABUTMENT ;
    PORT
      LAYER Metal1 ;
        RECT 1.585 0.300 1.815 0.865 ;
        RECT 0.000 -0.300 3.360 0.300 ;
    END
  END VSS
  OBS
      LAYER Metal1 ;
        RECT 0.245 2.815 0.630 3.390 ;
        RECT 0.245 2.580 2.255 2.815 ;
        RECT 0.245 0.800 0.475 2.580 ;
        RECT 1.970 1.830 2.255 2.580 ;
  END
END gf180mcu_fd_sc_mcu7t5v0__buf_1

MACRO gf180mcu_fd_sc_mcu7t5v0__inv_1
  CLASS core ;
  FOREIGN gf180mcu_fd_sc_mcu7t5v0__inv_1 ;
  ORIGIN 0.000 0.000 ;
  SIZE 2.240 BY 3.920 ;
  SYMMETRY X Y ;
  SITE unithd ;
  PIN I
    DIRECTION INPUT ;
    ANTENNAGATEAREA 1.102000 ;
    PORT
      LAYER Metal1 ;
        RECT 0.710 1.200 1.035 2.200 ;
    END
  END I
  PIN ZN
    DIRECTION OUTPUT ;
    ANTENNADIFFAREA 0.897600 ;
    PORT
      LAYER Metal1 ;
        RECT 1.265 0.530 1.595 3.390 ;
    END
  END ZN
  PIN VDD
    DIRECTION INOUT ;
    USE POWER ;
    SHAPE ABUTMENT ;
    PORT
      LAYER Metal1 ;
        RECT 0.000 3.620 2.240 4.220 ;
        RECT 0.345 2.530 0.575 3.620 ;
    END
  END VDD
  PIN VNW
    DIRECTION INOUT ;
    USE POWER ;
    PORT
      LAYER Nwell ;
        RECT -0.430 1.760 2.670 4.350 ;
    END
  END VNW
  PIN VPW
    DIRECTION INOUT ;
    USE GROUND ;
    PORT
      LAYER Pwell ;
        RECT -0.430 -0.430 2.670 1.760 ;
    END
  END VPW
  PIN VSS
    DIRECTION INOUT ;
    USE GROUND ;
    SHAPE ABUTMENT ;
    PORT
      LAYER Metal1 ;
        RECT 0.245 0.300 0.475 1.160 ;
        RECT 0.000 -0.300 2.240 0.300 ;
    END
  END VSS
END gf180mcu_fd_sc_mcu7t5v0__inv_1

MACRO gf180mcu_fd_sc_mcu7t5v0__nand2_1
  CLASS core ;
  FOREIGN gf180mcu_fd_sc_mcu7t5v0__nand2_1 ;
  ORIGIN 0.000 0.000 ;
  SIZE 2.800 BY 3.920 ;
  SYMMETRY X Y ;
  SITE unithd ;
  PIN A1
    DIRECTION INPUT ;
    ANTENNAGATEAREA 1.057000 ;
    PORT
      LAYER Metal1 ;
        RECT 1.240 1.440 2.055 1.820 ;
        RECT 1.240 0.555 1.605 1.440 ;
    END
  END A1
  PIN A2
    DIRECTION INPUT ;
    ANTENNAGATEAREA 1.057000 ;
    PORT
      LAYER Metal1 ;
        RECT 0.635 1.060 1.000 2.190 ;
    END
  END A2
  PIN ZN
    DIRECTION OUTPUT ;
    ANTENNADIFFAREA 0.948400 ;
    PORT
      LAYER Metal1 ;
        RECT 1.270 2.300 1.500 3.380 ;
        RECT 1.270 2.070 2.680 2.300 ;
        RECT 2.290 0.530 2.680 2.070 ;
    END
  END ZN
  PIN VDD
    DIRECTION INOUT ;
    USE POWER ;
    SHAPE ABUTMENT ;
    PORT
      LAYER Metal1 ;
        RECT 0.000 3.620 2.800 4.220 ;
        RECT 0.250 2.530 0.480 3.620 ;
        RECT 2.290 2.530 2.520 3.620 ;
    END
  END VDD
  PIN VNW
    DIRECTION INOUT ;
    USE POWER ;
    PORT
      LAYER Nwell ;
        RECT -0.430 1.760 3.230 4.350 ;
    END
  END VNW
  PIN VPW
    DIRECTION INOUT ;
    USE GROUND ;
    PORT
      LAYER Pwell ;
        RECT -0.430 -0.430 3.230 1.760 ;
    END
  END VPW
  PIN VSS
    DIRECTION INOUT ;
    USE GROUND ;
    SHAPE ABUTMENT ;
    PORT
      LAYER Metal1 ;
        RECT 0.250 0.300 0.480 0.805 ;
        RECT 0.000 -0.300 2.800 0.300 ;
    END
  END VSS
END gf180mcu_fd_sc_mcu7t5v0__nand2_1

MACRO gf180mcu_fd_sc_mcu7t5v0__nor2_1
  CLASS core ;
  FOREIGN gf180mcu_fd_sc_mcu7t5v0__nor2_1 ;
  ORIGIN 0.000 0.000 ;
  SIZE 3.360 BY 3.920 ;
  SYMMETRY X Y ;
  SITE unithd ;
  PIN A1
    DIRECTION INPUT ;
    ANTENNAGATEAREA 0.949000 ;
    PORT
      LAYER Metal1 ;
        RECT 1.825 1.790 2.855 2.130 ;
        RECT 1.825 0.600 2.130 1.790 ;
    END
  END A1
  PIN A2
    DIRECTION INPUT ;
    ANTENNAGATEAREA 0.949000 ;
    PORT
      LAYER Metal1 ;
        RECT 0.705 1.180 1.010 3.320 ;
    END
  END A2
  PIN ZN
    DIRECTION OUTPUT ;
    ANTENNADIFFAREA 0.830600 ;
    PORT
      LAYER Metal1 ;
        RECT 2.385 2.680 2.665 3.380 ;
        RECT 1.240 2.360 2.665 2.680 ;
        RECT 1.240 0.600 1.595 2.360 ;
    END
  END ZN
  PIN VDD
    DIRECTION INOUT ;
    USE POWER ;
    SHAPE ABUTMENT ;
    PORT
      LAYER Metal1 ;
        RECT 0.000 3.620 3.360 4.220 ;
        RECT 0.245 2.530 0.475 3.620 ;
    END
  END VDD
  PIN VNW
    DIRECTION INOUT ;
    USE POWER ;
    PORT
      LAYER Nwell ;
        RECT -0.430 1.760 3.790 4.350 ;
    END
  END VNW
  PIN VPW
    DIRECTION INOUT ;
    USE GROUND ;
    PORT
      LAYER Pwell ;
        RECT -0.430 -0.430 3.790 1.760 ;
    END
  END VPW
  PIN VSS
    DIRECTION INOUT ;
    USE GROUND ;
    SHAPE ABUTMENT ;
    PORT
      LAYER Metal1 ;
        RECT 0.245 0.300 0.475 0.945 ;
        RECT 2.485 0.300 2.715 1.090 ;
        RECT 0.000 -0.300 3.360 0.300 ;
    END
  END VSS
END gf180mcu_fd_sc_mcu7t5v0__nor2_1

MACRO gf180mcu_fd_sc_mcu7t5v0__clkbuf_16
  CLASS core ;
  FOREIGN gf180mcu_fd_sc_mcu7t5v0__clkbuf_16 ;
  ORIGIN 0.000 0.000 ;
  SIZE 28.000 BY 3.920 ;
  SYMMETRY X Y ;
  SITE unithd ;
  PIN I
    DIRECTION INPUT ;
    ANTENNAGATEAREA 4.738000 ;
    PORT
      LAYER Metal1 ;
        RECT 0.370 1.740 8.310 2.150 ;
    END
  END I
  PIN Z
    DIRECTION OUTPUT ;
    ANTENNADIFFAREA 8.068800 ;
    PORT
      LAYER Metal1 ;
        RECT 10.505 3.000 10.735 3.390 ;
        RECT 12.645 3.000 12.875 3.390 ;
        RECT 14.885 3.000 15.115 3.390 ;
        RECT 17.125 3.000 17.355 3.390 ;
        RECT 19.365 3.000 19.595 3.390 ;
        RECT 21.605 3.000 21.835 3.390 ;
        RECT 23.845 3.000 24.075 3.390 ;
        RECT 26.085 3.000 26.315 3.390 ;
        RECT 10.505 2.420 26.315 3.000 ;
        RECT 17.985 1.535 18.885 2.420 ;
        RECT 10.505 1.215 26.415 1.535 ;
        RECT 10.505 0.690 10.735 1.215 ;
        RECT 12.745 0.690 12.975 1.215 ;
        RECT 14.985 0.690 15.215 1.215 ;
        RECT 17.225 0.690 17.455 1.215 ;
        RECT 19.465 0.690 19.695 1.215 ;
        RECT 21.705 0.690 21.935 1.215 ;
        RECT 23.945 0.690 24.175 1.215 ;
        RECT 26.185 0.690 26.415 1.215 ;
    END
  END Z
  PIN VDD
    DIRECTION INOUT ;
    USE POWER ;
    SHAPE ABUTMENT ;
    PORT
      LAYER Metal1 ;
        RECT 0.000 3.620 28.000 4.220 ;
        RECT 0.245 3.230 0.475 3.620 ;
        RECT 2.385 3.050 2.615 3.620 ;
        RECT 4.625 3.050 4.855 3.620 ;
        RECT 6.865 3.050 7.095 3.620 ;
        RECT 9.385 3.190 9.615 3.620 ;
        RECT 11.525 3.230 11.755 3.620 ;
        RECT 13.765 3.230 13.995 3.620 ;
        RECT 16.005 3.230 16.235 3.620 ;
        RECT 18.245 3.230 18.475 3.620 ;
        RECT 20.485 3.230 20.715 3.620 ;
        RECT 22.725 3.230 22.955 3.620 ;
        RECT 24.965 3.230 25.195 3.620 ;
        RECT 27.205 2.760 27.435 3.620 ;
    END
  END VDD
  PIN VNW
    DIRECTION INOUT ;
    USE POWER ;
    PORT
      LAYER Nwell ;
        RECT -0.430 1.760 28.430 4.350 ;
    END
  END VNW
  PIN VPW
    DIRECTION INOUT ;
    USE GROUND ;
    PORT
      LAYER Pwell ;
        RECT -0.430 -0.430 28.430 1.760 ;
    END
  END VPW
  PIN VSS
    DIRECTION INOUT ;
    USE GROUND ;
    SHAPE ABUTMENT ;
    PORT
      LAYER Metal1 ;
        RECT 2.430 0.300 2.770 1.040 ;
        RECT 4.670 0.300 5.010 1.040 ;
        RECT 6.910 0.300 7.250 1.040 ;
        RECT 9.330 0.300 9.670 0.960 ;
        RECT 11.570 0.300 11.910 0.985 ;
        RECT 13.810 0.300 14.150 0.985 ;
        RECT 16.050 0.300 16.390 0.985 ;
        RECT 18.290 0.300 18.630 0.985 ;
        RECT 20.530 0.300 20.870 0.985 ;
        RECT 22.770 0.300 23.110 0.985 ;
        RECT 25.010 0.300 25.350 0.985 ;
        RECT 27.250 0.300 27.590 0.985 ;
        RECT 0.000 -0.300 28.000 0.300 ;
    END
  END VSS
  OBS
      LAYER Metal1 ;
        RECT 1.265 2.760 1.495 3.390 ;
        RECT 3.505 2.760 3.735 3.390 ;
        RECT 5.745 2.760 5.975 3.390 ;
        RECT 7.985 2.760 8.215 3.390 ;
        RECT 1.265 2.530 8.850 2.760 ;
        RECT 8.620 2.065 8.850 2.530 ;
        RECT 8.620 1.765 17.160 2.065 ;
        RECT 19.740 1.765 27.160 2.065 ;
        RECT 8.620 1.500 8.850 1.765 ;
        RECT 1.365 1.270 8.850 1.500 ;
        RECT 1.365 0.740 1.595 1.270 ;
        RECT 3.605 0.740 3.835 1.270 ;
        RECT 5.845 0.740 6.075 1.270 ;
        RECT 8.085 0.740 8.315 1.270 ;
  END
END gf180mcu_fd_sc_mcu7t5v0__clkbuf_16

END LIBRARY
